VERSION 5.7 ;
BUSBITCHARS "[]" ;
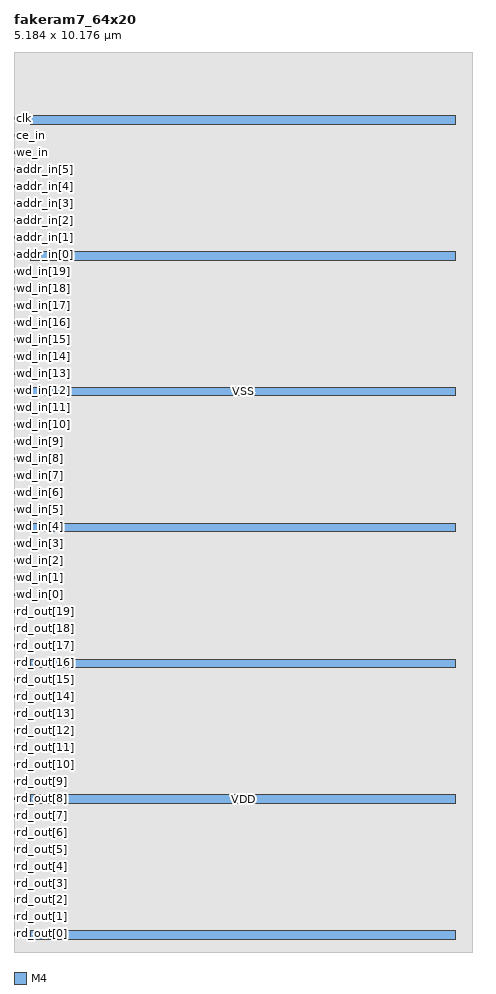
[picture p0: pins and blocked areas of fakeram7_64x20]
MACRO fakeram7_64x20
  FOREIGN fakeram7_64x20 0 0 ;
  SYMMETRY X Y R90 ;
  SIZE 5.184 BY 10.176 ;
  CLASS BLOCK ;
  PIN rd_out[0]
    DIRECTION OUTPUT ;
    USE SIGNAL ;
    SHAPE ABUTMENT ;
    PORT
      LAYER M4 ;
      RECT 0.000 0.192 0.024 0.216 ;
    END
  END rd_out[0]
  PIN rd_out[1]
    DIRECTION OUTPUT ;
    USE SIGNAL ;
    SHAPE ABUTMENT ;
    PORT
      LAYER M4 ;
      RECT 0.000 0.384 0.024 0.408 ;
    END
  END rd_out[1]
  PIN rd_out[2]
    DIRECTION OUTPUT ;
    USE SIGNAL ;
    SHAPE ABUTMENT ;
    PORT
      LAYER M4 ;
      RECT 0.000 0.576 0.024 0.600 ;
    END
  END rd_out[2]
  PIN rd_out[3]
    DIRECTION OUTPUT ;
    USE SIGNAL ;
    SHAPE ABUTMENT ;
    PORT
      LAYER M4 ;
      RECT 0.000 0.768 0.024 0.792 ;
    END
  END rd_out[3]
  PIN rd_out[4]
    DIRECTION OUTPUT ;
    USE SIGNAL ;
    SHAPE ABUTMENT ;
    PORT
      LAYER M4 ;
      RECT 0.000 0.960 0.024 0.984 ;
    END
  END rd_out[4]
  PIN rd_out[5]
    DIRECTION OUTPUT ;
    USE SIGNAL ;
    SHAPE ABUTMENT ;
    PORT
      LAYER M4 ;
      RECT 0.000 1.152 0.024 1.176 ;
    END
  END rd_out[5]
  PIN rd_out[6]
    DIRECTION OUTPUT ;
    USE SIGNAL ;
    SHAPE ABUTMENT ;
    PORT
      LAYER M4 ;
      RECT 0.000 1.344 0.024 1.368 ;
    END
  END rd_out[6]
  PIN rd_out[7]
    DIRECTION OUTPUT ;
    USE SIGNAL ;
    SHAPE ABUTMENT ;
    PORT
      LAYER M4 ;
      RECT 0.000 1.536 0.024 1.560 ;
    END
  END rd_out[7]
  PIN rd_out[8]
    DIRECTION OUTPUT ;
    USE SIGNAL ;
    SHAPE ABUTMENT ;
    PORT
      LAYER M4 ;
      RECT 0.000 1.728 0.024 1.752 ;
    END
  END rd_out[8]
  PIN rd_out[9]
    DIRECTION OUTPUT ;
    USE SIGNAL ;
    SHAPE ABUTMENT ;
    PORT
      LAYER M4 ;
      RECT 0.000 1.920 0.024 1.944 ;
    END
  END rd_out[9]
  PIN rd_out[10]
    DIRECTION OUTPUT ;
    USE SIGNAL ;
    SHAPE ABUTMENT ;
    PORT
      LAYER M4 ;
      RECT 0.000 2.112 0.024 2.136 ;
    END
  END rd_out[10]
  PIN rd_out[11]
    DIRECTION OUTPUT ;
    USE SIGNAL ;
    SHAPE ABUTMENT ;
    PORT
      LAYER M4 ;
      RECT 0.000 2.304 0.024 2.328 ;
    END
  END rd_out[11]
  PIN rd_out[12]
    DIRECTION OUTPUT ;
    USE SIGNAL ;
    SHAPE ABUTMENT ;
    PORT
      LAYER M4 ;
      RECT 0.000 2.496 0.024 2.520 ;
    END
  END rd_out[12]
  PIN rd_out[13]
    DIRECTION OUTPUT ;
    USE SIGNAL ;
    SHAPE ABUTMENT ;
    PORT
      LAYER M4 ;
      RECT 0.000 2.688 0.024 2.712 ;
    END
  END rd_out[13]
  PIN rd_out[14]
    DIRECTION OUTPUT ;
    USE SIGNAL ;
    SHAPE ABUTMENT ;
    PORT
      LAYER M4 ;
      RECT 0.000 2.880 0.024 2.904 ;
    END
  END rd_out[14]
  PIN rd_out[15]
    DIRECTION OUTPUT ;
    USE SIGNAL ;
    SHAPE ABUTMENT ;
    PORT
      LAYER M4 ;
      RECT 0.000 3.072 0.024 3.096 ;
    END
  END rd_out[15]
  PIN rd_out[16]
    DIRECTION OUTPUT ;
    USE SIGNAL ;
    SHAPE ABUTMENT ;
    PORT
      LAYER M4 ;
      RECT 0.000 3.264 0.024 3.288 ;
    END
  END rd_out[16]
  PIN rd_out[17]
    DIRECTION OUTPUT ;
    USE SIGNAL ;
    SHAPE ABUTMENT ;
    PORT
      LAYER M4 ;
      RECT 0.000 3.456 0.024 3.480 ;
    END
  END rd_out[17]
  PIN rd_out[18]
    DIRECTION OUTPUT ;
    USE SIGNAL ;
    SHAPE ABUTMENT ;
    PORT
      LAYER M4 ;
      RECT 0.000 3.648 0.024 3.672 ;
    END
  END rd_out[18]
  PIN rd_out[19]
    DIRECTION OUTPUT ;
    USE SIGNAL ;
    SHAPE ABUTMENT ;
    PORT
      LAYER M4 ;
      RECT 0.000 3.840 0.024 3.864 ;
    END
  END rd_out[19]
  PIN wd_in[0]
    DIRECTION INPUT ;
    USE SIGNAL ;
    SHAPE ABUTMENT ;
    PORT
      LAYER M4 ;
      RECT 0.000 4.032 0.024 4.056 ;
    END
  END wd_in[0]
  PIN wd_in[1]
    DIRECTION INPUT ;
    USE SIGNAL ;
    SHAPE ABUTMENT ;
    PORT
      LAYER M4 ;
      RECT 0.000 4.224 0.024 4.248 ;
    END
  END wd_in[1]
  PIN wd_in[2]
    DIRECTION INPUT ;
    USE SIGNAL ;
    SHAPE ABUTMENT ;
    PORT
      LAYER M4 ;
      RECT 0.000 4.416 0.024 4.440 ;
    END
  END wd_in[2]
  PIN wd_in[3]
    DIRECTION INPUT ;
    USE SIGNAL ;
    SHAPE ABUTMENT ;
    PORT
      LAYER M4 ;
      RECT 0.000 4.608 0.024 4.632 ;
    END
  END wd_in[3]
  PIN wd_in[4]
    DIRECTION INPUT ;
    USE SIGNAL ;
    SHAPE ABUTMENT ;
    PORT
      LAYER M4 ;
      RECT 0.000 4.800 0.024 4.824 ;
    END
  END wd_in[4]
  PIN wd_in[5]
    DIRECTION INPUT ;
    USE SIGNAL ;
    SHAPE ABUTMENT ;
    PORT
      LAYER M4 ;
      RECT 0.000 4.992 0.024 5.016 ;
    END
  END wd_in[5]
  PIN wd_in[6]
    DIRECTION INPUT ;
    USE SIGNAL ;
    SHAPE ABUTMENT ;
    PORT
      LAYER M4 ;
      RECT 0.000 5.184 0.024 5.208 ;
    END
  END wd_in[6]
  PIN wd_in[7]
    DIRECTION INPUT ;
    USE SIGNAL ;
    SHAPE ABUTMENT ;
    PORT
      LAYER M4 ;
      RECT 0.000 5.376 0.024 5.400 ;
    END
  END wd_in[7]
  PIN wd_in[8]
    DIRECTION INPUT ;
    USE SIGNAL ;
    SHAPE ABUTMENT ;
    PORT
      LAYER M4 ;
      RECT 0.000 5.568 0.024 5.592 ;
    END
  END wd_in[8]
  PIN wd_in[9]
    DIRECTION INPUT ;
    USE SIGNAL ;
    SHAPE ABUTMENT ;
    PORT
      LAYER M4 ;
      RECT 0.000 5.760 0.024 5.784 ;
    END
  END wd_in[9]
  PIN wd_in[10]
    DIRECTION INPUT ;
    USE SIGNAL ;
    SHAPE ABUTMENT ;
    PORT
      LAYER M4 ;
      RECT 0.000 5.952 0.024 5.976 ;
    END
  END wd_in[10]
  PIN wd_in[11]
    DIRECTION INPUT ;
    USE SIGNAL ;
    SHAPE ABUTMENT ;
    PORT
      LAYER M4 ;
      RECT 0.000 6.144 0.024 6.168 ;
    END
  END wd_in[11]
  PIN wd_in[12]
    DIRECTION INPUT ;
    USE SIGNAL ;
    SHAPE ABUTMENT ;
    PORT
      LAYER M4 ;
      RECT 0.000 6.336 0.024 6.360 ;
    END
  END wd_in[12]
  PIN wd_in[13]
    DIRECTION INPUT ;
    USE SIGNAL ;
    SHAPE ABUTMENT ;
    PORT
      LAYER M4 ;
      RECT 0.000 6.528 0.024 6.552 ;
    END
  END wd_in[13]
  PIN wd_in[14]
    DIRECTION INPUT ;
    USE SIGNAL ;
    SHAPE ABUTMENT ;
    PORT
      LAYER M4 ;
      RECT 0.000 6.720 0.024 6.744 ;
    END
  END wd_in[14]
  PIN wd_in[15]
    DIRECTION INPUT ;
    USE SIGNAL ;
    SHAPE ABUTMENT ;
    PORT
      LAYER M4 ;
      RECT 0.000 6.912 0.024 6.936 ;
    END
  END wd_in[15]
  PIN wd_in[16]
    DIRECTION INPUT ;
    USE SIGNAL ;
    SHAPE ABUTMENT ;
    PORT
      LAYER M4 ;
      RECT 0.000 7.104 0.024 7.128 ;
    END
  END wd_in[16]
  PIN wd_in[17]
    DIRECTION INPUT ;
    USE SIGNAL ;
    SHAPE ABUTMENT ;
    PORT
      LAYER M4 ;
      RECT 0.000 7.296 0.024 7.320 ;
    END
  END wd_in[17]
  PIN wd_in[18]
    DIRECTION INPUT ;
    USE SIGNAL ;
    SHAPE ABUTMENT ;
    PORT
      LAYER M4 ;
      RECT 0.000 7.488 0.024 7.512 ;
    END
  END wd_in[18]
  PIN wd_in[19]
    DIRECTION INPUT ;
    USE SIGNAL ;
    SHAPE ABUTMENT ;
    PORT
      LAYER M4 ;
      RECT 0.000 7.680 0.024 7.704 ;
    END
  END wd_in[19]
  PIN addr_in[0]
    DIRECTION INPUT ;
    USE SIGNAL ;
    SHAPE ABUTMENT ;
    PORT
      LAYER M4 ;
      RECT 0.000 7.872 0.024 7.896 ;
    END
  END addr_in[0]
  PIN addr_in[1]
    DIRECTION INPUT ;
    USE SIGNAL ;
    SHAPE ABUTMENT ;
    PORT
      LAYER M4 ;
      RECT 0.000 8.064 0.024 8.088 ;
    END
  END addr_in[1]
  PIN addr_in[2]
    DIRECTION INPUT ;
    USE SIGNAL ;
    SHAPE ABUTMENT ;
    PORT
      LAYER M4 ;
      RECT 0.000 8.256 0.024 8.280 ;
    END
  END addr_in[2]
  PIN addr_in[3]
    DIRECTION INPUT ;
    USE SIGNAL ;
    SHAPE ABUTMENT ;
    PORT
      LAYER M4 ;
      RECT 0.000 8.448 0.024 8.472 ;
    END
  END addr_in[3]
  PIN addr_in[4]
    DIRECTION INPUT ;
    USE SIGNAL ;
    SHAPE ABUTMENT ;
    PORT
      LAYER M4 ;
      RECT 0.000 8.640 0.024 8.664 ;
    END
  END addr_in[4]
  PIN addr_in[5]
    DIRECTION INPUT ;
    USE SIGNAL ;
    SHAPE ABUTMENT ;
    PORT
      LAYER M4 ;
      RECT 0.000 8.832 0.024 8.856 ;
    END
  END addr_in[5]
  PIN we_in
    DIRECTION INPUT ;
    USE SIGNAL ;
    SHAPE ABUTMENT ;
    PORT
      LAYER M4 ;
      RECT 0.000 9.024 0.024 9.048 ;
    END
  END we_in
  PIN ce_in
    DIRECTION INPUT ;
    USE SIGNAL ;
    SHAPE ABUTMENT ;
    PORT
      LAYER M4 ;
      RECT 0.000 9.216 0.024 9.240 ;
    END
  END ce_in
  PIN clk
    DIRECTION INPUT ;
    USE SIGNAL ;
    SHAPE ABUTMENT ;
    PORT
      LAYER M4 ;
      RECT 0.000 9.408 0.024 9.432 ;
    END
  END clk
  PIN VSS
    DIRECTION INOUT ;
    USE GROUND ;
    PORT
      LAYER M4 ;
      RECT 0.192 0.144 4.992 0.240 ;
      RECT 0.192 3.216 4.992 3.312 ;
      RECT 0.192 6.288 4.992 6.384 ;
      RECT 0.192 9.360 4.992 9.456 ;
    END
  END VSS
  PIN VDD
    DIRECTION INOUT ;
    USE POWER ;
    PORT
      LAYER M4 ;
      RECT 0.192 1.680 4.992 1.776 ;
      RECT 0.192 4.752 4.992 4.848 ;
      RECT 0.192 7.824 4.992 7.920 ;
    END
  END VDD
  OBS
    LAYER M1 ;
    RECT 0 0 5.184 10.176 ;
    LAYER M2 ;
    RECT 0 0 5.184 10.176 ;
    LAYER M3 ;
    RECT 0 0 5.184 10.176 ;
    LAYER M4 ;
    RECT 0 0 5.184 10.176 ;
  END
END fakeram7_64x20

END LIBRARY
